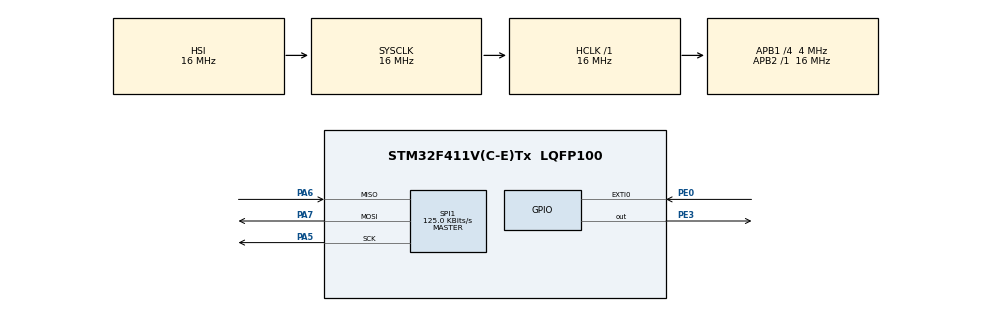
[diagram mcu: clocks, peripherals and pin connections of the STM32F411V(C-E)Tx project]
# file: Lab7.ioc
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Mcu.Family=STM32F4
Mcu.Name=STM32F411V(C-E)Tx
Mcu.Package=LQFP100
NVIC.EXTI0_IRQn=true\:0\:0\:false\:false\:true\:true\:true\:true
NVIC.PriorityGroup=NVIC_PRIORITYGROUP_0
PA5.Mode=Full_Duplex_Master
PA5.Signal=SPI1_SCK
PA6.Mode=Full_Duplex_Master
PA6.Signal=SPI1_MISO
PA7.Mode=Full_Duplex_Master
PA7.Signal=SPI1_MOSI
PE0.Signal=GPXTI0
PE3.Signal=GPIO_Output
ProjectManager.HeapSize=0x200
ProjectManager.StackSize=0x400
ProjectManager.TargetToolchain=STM32CubeIDE
RCC.48MHZClocksFreq_Value=96000000
RCC.AHBFreq_Value=16000000
RCC.APB1CLKDivider=RCC_HCLK_DIV4
RCC.APB1Freq_Value=4000000
RCC.APB1TimFreq_Value=8000000
RCC.APB2Freq_Value=16000000
RCC.APB2TimFreq_Value=16000000
RCC.CortexFreq_Value=16000000
RCC.HCLKFreq_Value=16000000
RCC.HSE_VALUE=8000000
RCC.HSI_VALUE=16000000
RCC.PLLI2SM=5
RCC.PLLI2SN=200
RCC.PLLM=4
RCC.PLLP=RCC_PLLP_DIV4
RCC.PLLQ=8
RCC.SYSCLKFreq_VALUE=16000000
RCC.VCOOutputFreq_Value=768000000
SPI1.BaudRatePrescaler=SPI_BAUDRATEPRESCALER_128
SPI1.CalculateBaudRate=125.0 KBits/s
SPI1.Direction=SPI_DIRECTION_2LINES
SPI1.Mode=SPI_MODE_MASTER
SPI1.VirtualType=VM_MASTER
board=STM32F411E-DISCO

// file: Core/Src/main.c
/* USER CODE BEGIN Header */
/**
  ******************************************************************************
  * @file           : main.c
  * @brief          : Main program body
  ******************************************************************************
  * @attention
  *
  * Copyright (c) 2023 STMicroelectronics.
  * All rights reserved.
  *
  * This software is licensed under terms that can be found in the LICENSE file
  * in the root directory of this software component.
  * If no LICENSE file comes with this software, it is provided AS-IS.
  *
  ******************************************************************************
  */
/* USER CODE END Header */
#include "main.h"
#include "stm32f4xx_hal.h"
/* USER CODE BEGIN Includes */

#include "MY_LIS3DSH.h"

/* USER CODE END Includes */

SPI_HandleTypeDef hspi1;

/* USER CODE BEGIN PV */

LIS3DSH_DataScaled myData;
uint8_t drdyFlag = 0;

/* USER CODE END PV */

void SystemClock_Config(void);
static void MX_GPIO_Init(void);
static void MX_SPI1_Init(void);

/* USER CODE BEGIN 0 */

void HAL_GPIO_EXTI_Callback(uint16_t GPIO_Pin)
{
  /* Prevent unused argument(s) compilation warning */
  UNUSED(GPIO_Pin);
  /* NOTE: This function Should not be modified, when the callback is needed,
           the HAL_GPIO_EXTI_Callback could be implemented in the user file
   */

  drdyFlag = 1;
}
/* USER CODE END 0 */

int main(void)
{

  /* MCU Configuration--------------------------------------------------------*/

  /* Reset of all peripherals, Initializes the Flash interface and the Systick. */
  HAL_Init();

  /* Configure the system clock */
  SystemClock_Config();

  /* Initialize all configured peripherals */
  MX_GPIO_Init();
  MX_SPI1_Init();
  /* USER CODE BEGIN 2 */

  LIS3DSH_InitTypeDef myAccConfigDef;

  myAccConfigDef.dataRate = LIS3DSH_DATARATE_25;
  myAccConfigDef.fullScale = LIS3DSH_FULLSCALE_4;
  myAccConfigDef.antiAliasingBW = LIS3DSH_FILTER_BW_50;
  myAccConfigDef.enableAxes = LIS3DSH_XYZ_ENABLE;
  myAccConfigDef.interruptEnable = true;
  LIS3DSH_Init(&hspi1, &myAccConfigDef);

  LIS3DSH_X_calibrate(-1000.0, 980.0);
  LIS3DSH_Y_calibrate(-1020.0, 1040.0);
  LIS3DSH_Z_calibrate(-920.0, 1040.0);

  /* USER CODE END 2 */

  /* Infinite loop */
  /* USER CODE BEGIN WHILE */
  while (1)
  {
  	if(drdyFlag == 1)
  	  {
  		  myData = LIS3DSH_GetDataScaled();
  		  if(myData.x<-50){
  			  HAL_GPIO_WritePin(GPIOD, GPIO_PIN_12, GPIO_PIN_SET);
  			  HAL_GPIO_WritePin(GPIOD, GPIO_PIN_14, GPIO_PIN_RESET);
  		  }
  		  else if(myData.x>50){
  			  HAL_GPIO_WritePin(GPIOD, GPIO_PIN_12, GPIO_PIN_RESET);
  			  HAL_GPIO_WritePin(GPIOD, GPIO_PIN_14, GPIO_PIN_SET);
  			  }
  		  else {
  			HAL_GPIO_WritePin(GPIOD, GPIO_PIN_12, GPIO_PIN_RESET);
  			HAL_GPIO_WritePin(GPIOD, GPIO_PIN_14, GPIO_PIN_RESET);
  		  }

  		if(myData.y<-50){
  			HAL_GPIO_WritePin(GPIOD, GPIO_PIN_15, GPIO_PIN_SET);
  			HAL_GPIO_WritePin(GPIOD, GPIO_PIN_13, GPIO_PIN_RESET);
  		}
  		else if(myData.y>50){
  			HAL_GPIO_WritePin(GPIOD, GPIO_PIN_15, GPIO_PIN_RESET);
  			HAL_GPIO_WritePin(GPIOD, GPIO_PIN_13, GPIO_PIN_SET);
  			  			  }
  		else {
  			HAL_GPIO_WritePin(GPIOD, GPIO_PIN_15, GPIO_PIN_RESET);
  			HAL_GPIO_WritePin(GPIOD, GPIO_PIN_13, GPIO_PIN_RESET);
  			}
  		  drdyFlag = 0;
  	  }
    /* USER CODE END WHILE */

  }
}

void SystemClock_Config(void)
{
  RCC_OscInitTypeDef RCC_OscInitStruct = {0};
  RCC_ClkInitTypeDef RCC_ClkInitStruct = {0};

  /** Configure the main internal regulator output voltage
  */
  __HAL_RCC_PWR_CLK_ENABLE();
  __HAL_PWR_VOLTAGESCALING_CONFIG(PWR_REGULATOR_VOLTAGE_SCALE1);

  /** Initializes the RCC Oscillators according to the specified parameters
  * in the RCC_OscInitTypeDef structure.
  */
  RCC_OscInitStruct.OscillatorType = RCC_OSCILLATORTYPE_HSI;
  RCC_OscInitStruct.HSIState = RCC_HSI_ON;
  RCC_OscInitStruct.HSICalibrationValue = RCC_HSICALIBRATION_DEFAULT;
  RCC_OscInitStruct.PLL.PLLState = RCC_PLL_NONE;
  if (HAL_RCC_OscConfig(&RCC_OscInitStruct) != HAL_OK)
  {
    Error_Handler();
  }

  /** Initializes the CPU, AHB and APB buses clocks
  */
  RCC_ClkInitStruct.ClockType = RCC_CLOCKTYPE_HCLK|RCC_CLOCKTYPE_SYSCLK
                              |RCC_CLOCKTYPE_PCLK1|RCC_CLOCKTYPE_PCLK2;
  RCC_ClkInitStruct.SYSCLKSource = RCC_SYSCLKSOURCE_HSI;
  RCC_ClkInitStruct.AHBCLKDivider = RCC_SYSCLK_DIV1;
  RCC_ClkInitStruct.APB1CLKDivider = RCC_HCLK_DIV4;
  RCC_ClkInitStruct.APB2CLKDivider = RCC_HCLK_DIV1;

  if (HAL_RCC_ClockConfig(&RCC_ClkInitStruct, FLASH_LATENCY_0) != HAL_OK)
  {
    Error_Handler();
  }
}

static void MX_SPI1_Init(void)
{

  /* SPI1 parameter configuration*/
  hspi1.Instance = SPI1;
  hspi1.Init.Mode = SPI_MODE_MASTER;
  hspi1.Init.Direction = SPI_DIRECTION_2LINES;
  hspi1.Init.DataSize = SPI_DATASIZE_8BIT;
  hspi1.Init.CLKPolarity = SPI_POLARITY_LOW;
  hspi1.Init.CLKPhase = SPI_PHASE_1EDGE;
  hspi1.Init.NSS = SPI_NSS_SOFT;
  hspi1.Init.BaudRatePrescaler = SPI_BAUDRATEPRESCALER_32;
  hspi1.Init.FirstBit = SPI_FIRSTBIT_MSB;
  hspi1.Init.TIMode = SPI_TIMODE_DISABLE;
  hspi1.Init.CRCCalculation = SPI_CRCCALCULATION_DISABLE;
  hspi1.Init.CRCPolynomial = 10;
  if (HAL_SPI_Init(&hspi1) != HAL_OK)
  {
    Error_Handler();
  }

}

static void MX_GPIO_Init(void)
{
  GPIO_InitTypeDef GPIO_InitStruct = {0};

  /* GPIO Ports Clock Enable */
  __HAL_RCC_GPIOE_CLK_ENABLE();
  __HAL_RCC_GPIOA_CLK_ENABLE();
  __HAL_RCC_GPIOD_CLK_ENABLE();

  /*Configure GPIO pin Output Level */
  HAL_GPIO_WritePin(GPIOE, GPIO_PIN_3, GPIO_PIN_RESET);

  /*Configure GPIO pin Output Level */
  HAL_GPIO_WritePin(GPIOD, GPIO_PIN_12|GPIO_PIN_13|GPIO_PIN_14|GPIO_PIN_15, GPIO_PIN_RESET);

  /*Configure GPIO pin : PE3 */
  GPIO_InitStruct.Pin = GPIO_PIN_3;
  GPIO_InitStruct.Mode = GPIO_MODE_OUTPUT_PP;
  GPIO_InitStruct.Pull = GPIO_NOPULL;
  GPIO_InitStruct.Speed = GPIO_SPEED_FREQ_LOW;
  HAL_GPIO_Init(GPIOE, &GPIO_InitStruct);

  /*Configure GPIO pins : PD12 PD13 PD14 PD15 */
  GPIO_InitStruct.Pin = GPIO_PIN_12|GPIO_PIN_13|GPIO_PIN_14|GPIO_PIN_15;
  GPIO_InitStruct.Mode = GPIO_MODE_OUTPUT_PP;
  GPIO_InitStruct.Pull = GPIO_NOPULL;
  GPIO_InitStruct.Speed = GPIO_SPEED_FREQ_LOW;
  HAL_GPIO_Init(GPIOD, &GPIO_InitStruct);

  /*Configure GPIO pin : PE0 */
  GPIO_InitStruct.Pin = GPIO_PIN_0;
  GPIO_InitStruct.Mode = GPIO_MODE_IT_RISING;
  GPIO_InitStruct.Pull = GPIO_NOPULL;
  HAL_GPIO_Init(GPIOE, &GPIO_InitStruct);

  /* EXTI interrupt init*/
  HAL_NVIC_SetPriority(EXTI0_IRQn, 0, 0);
  HAL_NVIC_EnableIRQ(EXTI0_IRQn);

}

void Error_Handler(void)
{
  __disable_irq();
  while (1)
  {
  }
}
